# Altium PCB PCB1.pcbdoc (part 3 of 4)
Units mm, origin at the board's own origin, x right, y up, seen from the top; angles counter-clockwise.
Board outline 96.27 x 122.17 mm, 4 copper layers (Top Layer, Inner1, Inner2, Bottom Layer); 167 components, 166 nets, 783 pads, 353 vias.

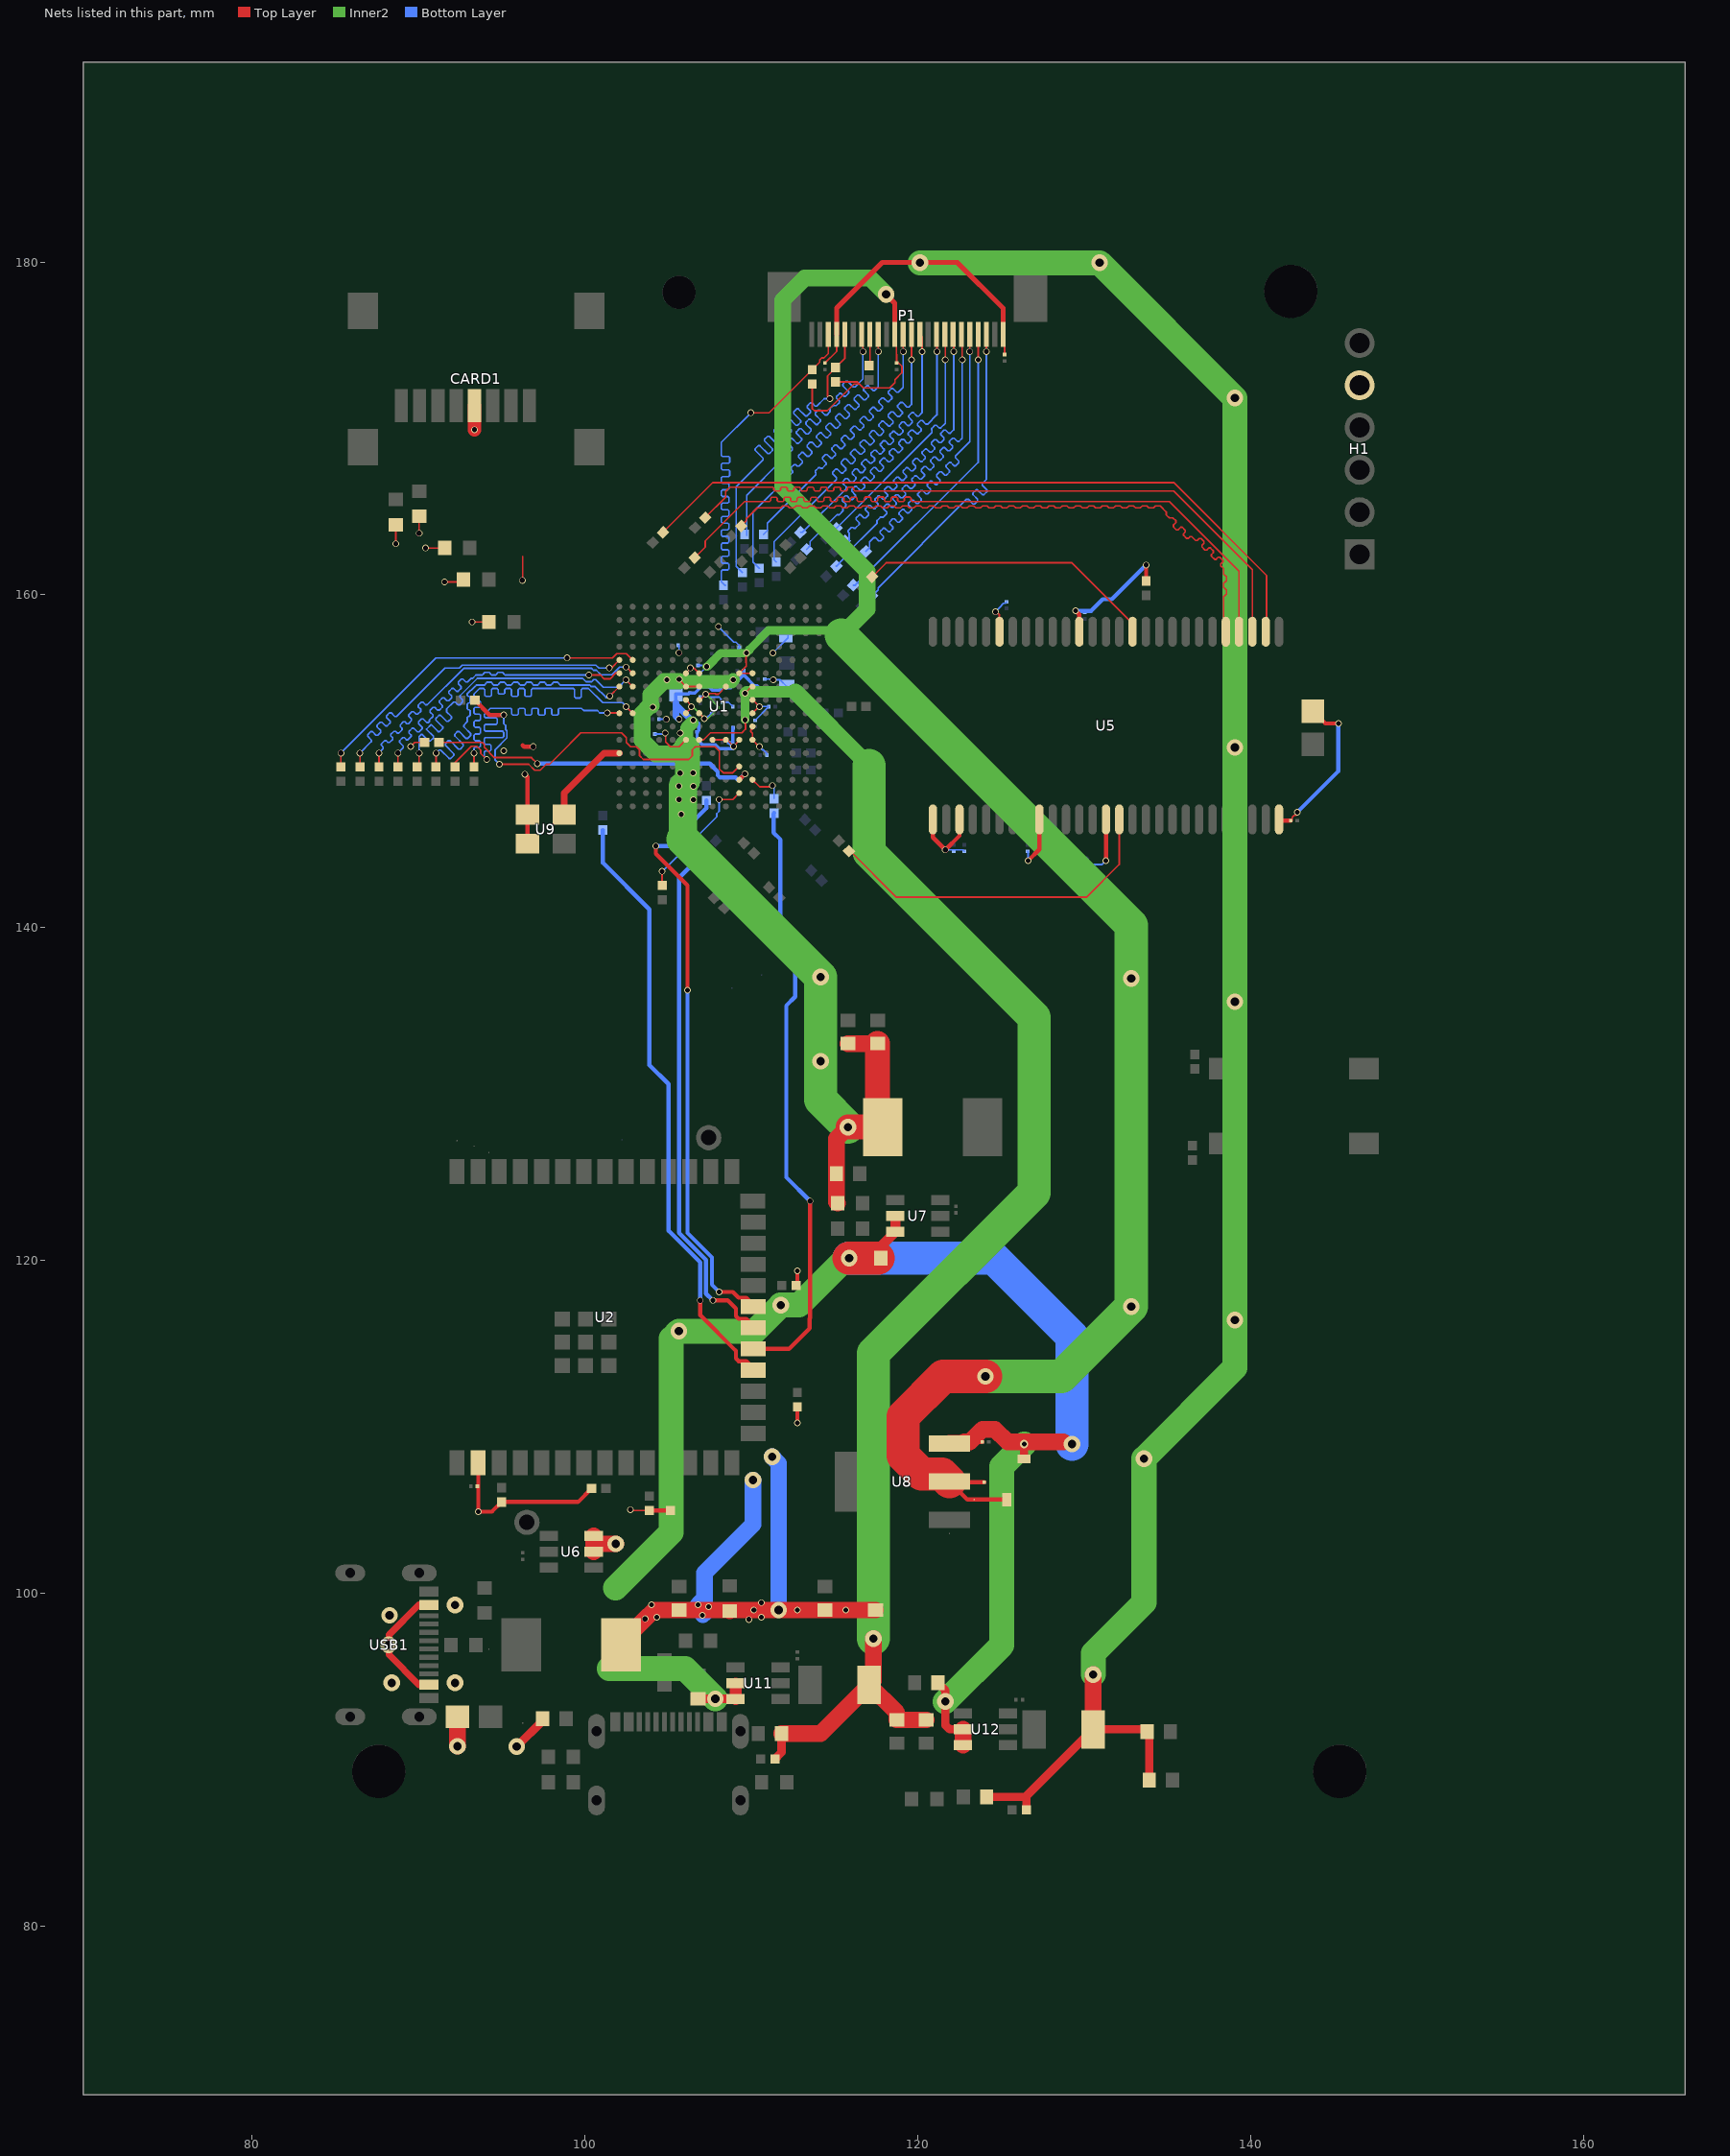
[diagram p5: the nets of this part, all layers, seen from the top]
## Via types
v1: diameter 0.4, hole 0.3, Top Layer to Bottom Layer, 318 vias
v2: diameter 1, hole 0.5, Top Layer to Bottom Layer, 34 vias
v3: diameter 0.5, hole 0.3, Top Layer to Bottom Layer, 1 vias

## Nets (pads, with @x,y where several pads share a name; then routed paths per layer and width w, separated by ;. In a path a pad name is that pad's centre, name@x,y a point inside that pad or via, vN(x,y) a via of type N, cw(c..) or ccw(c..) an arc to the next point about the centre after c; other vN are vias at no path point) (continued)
$1N75103: R65.1 U5.32 | length 40.7
  Top Layer w0.1: R65.1@109.399,164.136 109.706,164.443 109.706,164.57 110.363,165.227 111.775,165.227 111.902,165.354 112.175,165.354 112.302,165.227 112.575,165.227 112.702,165.354 112.975,165.354 113.102,165.227 113.375,165.227 113.502,165.354 113.775,165.354 113.902,165.227 114.175,165.227 114.302,165.354 114.575,165.354 114.702,165.227 114.975,165.227 115.102,165.354 115.375,165.354 115.502,165.227 115.775,165.227 115.902,165.354 116.175,165.354 116.302,165.227 116.575,165.227 116.702,165.354 116.975,165.354 117.102,165.227 117.375,165.227 117.502,165.354 117.775,165.354 117.902,165.227 118.175,165.227 118.302,165.354 118.575,165.354 118.702,165.227 118.975,165.227 119.102,165.354 119.375,165.354 119.502,165.227 119.775,165.227 119.902,165.354 120.175,165.354 120.302,165.227 120.575,165.227 120.702,165.354 120.975,165.354 121.102,165.227 121.375,165.227 121.502,165.354 121.775,165.354 121.902,165.227 122.175,165.227 122.302,165.354 122.575,165.354 122.702,165.227 122.975,165.227 123.102,165.354 123.375,165.354 123.502,165.227 123.775,165.227 123.902,165.354 124.175,165.354 124.302,165.227 124.575,165.227 124.702,165.354 124.975,165.354 125.102,165.227 125.375,165.227 125.502,165.354 125.775,165.354 125.902,165.227 126.175,165.227 126.302,165.354 126.575,165.354 126.702,165.227 126.975,165.227 127.102,165.354 127.375,165.354 127.502,165.227 127.775,165.227 127.902,165.354 128.175,165.354 128.302,165.227 128.575,165.227 128.702,165.354 128.975,165.354 129.102,165.227 129.375,165.227 129.502,165.354 129.775,165.354 129.902,165.227 130.175,165.227 130.302,165.354 130.575,165.354 130.702,165.227 130.975,165.227 131.102,165.354 131.375,165.354 131.502,165.227 131.775,165.227 131.902,165.354 132.175,165.354 132.302,165.227 132.575,165.227 132.702,165.354 132.975,165.354 133.102,165.227 133.375,165.227 133.502,165.354 133.775,165.354 133.902,165.227 134.175,165.227 134.302,165.354 134.575,165.354 134.947,164.982 134.947,164.803 135.13,164.62 135.23,164.62 135.242,164.632 135.342,164.632 135.525,164.449 135.525,164.349 135.371,164.195 135.371,164.095 135.553,163.912 135.653,163.912 135.808,164.066 135.908,164.066 136.091,163.883 136.091,163.783 135.985,163.678 135.985,163.578 136.168,163.395 136.268,163.395 136.373,163.501 136.473,163.501 136.707,163.267 136.807,163.267 136.926,163.386 137.026,163.386 137.208,163.203 137.208,163.103 137.09,162.984 137.09,162.884 137.272,162.702 137.372,162.702 137.491,162.82 137.591,162.82 137.774,162.638 137.774,162.538 137.655,162.419 137.655,162.319 137.838,162.136 137.938,162.136 138.057,162.255 138.157,162.255 138.34,162.072 138.34,161.972 138.221,161.853 138.221,161.753 138.391,161.583 138.391,161.243 138.462,161.172 138.486,161.172 138.557,161.101 138.557,160.843 138.486,160.772 138.462,160.772 138.391,160.701 138.391,160.443 138.462,160.372 138.486,160.372 138.557,160.301 138.557,160.043 138.486,159.972 138.462,159.972 138.391,159.901 138.391,157.915 U5.32@138.518,157.788
$1N75146: R66.1 U5.31 | length 43.6
  Top Layer w0.1: R66.1@106.605,162.231 107.235,162.861 107.235,163.242 109.601,165.608 111.096,165.608 111.167,165.679 111.167,165.791 111.237,165.862 111.496,165.862 111.567,165.791 111.567,165.679 111.637,165.608 111.896,165.608 111.967,165.679 111.967,165.791 112.037,165.862 112.296,165.862 112.367,165.791 112.367,165.679 112.437,165.608 112.696,165.608 112.767,165.679 112.767,165.791 112.837,165.862 113.096,165.862 113.167,165.791 113.167,165.679 113.237,165.608 113.496,165.608 113.567,165.679 113.567,165.791 113.637,165.862 113.896,165.862 113.967,165.791 113.967,165.679 114.037,165.608 114.296,165.608 114.367,165.679 114.367,165.791 114.437,165.862 114.696,165.862 114.767,165.791 114.767,165.679 114.837,165.608 115.096,165.608 115.167,165.679 115.167,165.791 115.237,165.862 115.496,165.862 115.567,165.791 115.567,165.679 115.637,165.608 115.896,165.608 115.967,165.679 115.967,165.791 116.037,165.862 116.296,165.862 116.367,165.791 116.367,165.679 116.437,165.608 116.732,165.608 116.803,165.679 116.803,165.809 116.874,165.879 117.132,165.879 117.203,165.809 117.203,165.679 117.274,165.608 117.532,165.608 117.603,165.679 117.603,165.809 117.674,165.879 117.932,165.879 118.003,165.809 118.003,165.679 118.074,165.608 118.332,165.608 118.403,165.679 118.403,165.809 118.474,165.879 118.732,165.879 118.803,165.809 118.803,165.679 118.874,165.608 119.132,165.608 119.203,165.679 119.203,165.809 119.274,165.879 119.532,165.879 119.603,165.809 119.603,165.679 119.674,165.608 135.128,165.608 139.318,161.418 U5.31@139.318,157.788
$1N75189: R67.1 U5.30 | length 41.4
  Top Layer w0.1: R67.1@107.24,164.644 108.458,165.862 108.458,166.214 108.712,166.468 111.296,166.468 111.367,166.397 111.367,166.314 111.438,166.243 111.696,166.243 111.767,166.314 111.767,166.397 111.838,166.468 112.096,166.468 112.167,166.397 112.167,166.314 112.238,166.243 112.496,166.243 112.567,166.314 112.567,166.397 112.638,166.468 112.896,166.468 112.967,166.397 112.967,166.314 113.038,166.243 113.296,166.243 113.367,166.314 113.367,166.397 113.438,166.468 113.696,166.468 113.767,166.397 113.767,166.314 113.838,166.243 114.096,166.243 114.167,166.314 114.167,166.397 114.238,166.468 114.496,166.468 114.567,166.397 114.567,166.314 114.638,166.243 114.896,166.243 114.967,166.314 114.967,166.397 115.038,166.468 115.296,166.468 115.367,166.397 115.367,166.314 115.438,166.243 115.696,166.243 115.767,166.314 115.767,166.397 115.838,166.468 116.096,166.468 116.167,166.397 116.167,166.314 116.238,166.243 135.382,166.243 140.118,161.507 U5.30@140.118,157.788
$1N75232: R68.1 U5.29 | length 43.2
  Top Layer w0.1: R68.1@104.7,163.755 107.696,166.751 135.382,166.751 140.97,161.163 140.97,157.84 U5.29@140.918,157.788
$1N75310: R69.2 U5.15 | length 20.9
  Top Layer w0.1: R69.2@115.876,144.601 115.965,144.601 118.735,141.831 130.147,141.831 132.118,143.802 U5.15@132.118,146.504
$1N75353: R70.1 U5.39 | length 18
  Top Layer w0.1: R70.1@117.273,161.088 118.11,161.925 129.27,161.925 132.918,158.277 U5.39@132.918,157.788
$1N78998: P1.7 R73.2 | length 21.8
  Top Layer w0.1: P1.7@116.634,175.655 116.713,175.577 v1(116.713,174.625)
  Bottom Layer w0.1: R73.2@109.728,163.576 109.728,165.989 111.898,168.159 111.898,168.259 111.589,168.568 111.589,168.668 111.772,168.851 111.872,168.851 112.181,168.542 112.281,168.542 112.464,168.725 112.464,168.825 112.155,169.134 112.155,169.234 112.337,169.417 112.437,169.417 112.747,169.108 112.847,169.108 113.029,169.29 113.029,169.39 112.72,169.7 112.72,169.8 112.903,169.982 113.003,169.982 113.312,169.673 113.412,169.673 113.595,169.856 113.595,169.956 113.286,170.265 113.286,170.365 113.469,170.548 113.569,170.548 113.878,170.239 113.978,170.239 114.161,170.422 114.161,170.522 113.852,170.831 113.852,170.931 114.035,171.114 114.135,171.114 114.444,170.805 114.544,170.805 114.73,170.991 114.73,171.184 114.917,171.37 115.109,171.37 115.292,171.553 115.292,171.653 115.126,171.819 115.126,171.919 115.309,172.102 115.409,172.102 115.575,171.936 115.675,171.936 115.858,172.119 115.858,172.219 115.513,172.563 115.513,172.663 115.696,172.846 115.796,172.846 116.141,172.502 116.241,172.502 116.713,172.974 v1(116.713,174.625)
$1N79046: P1.8 R35.1 | length 1.9
  Top Layer w0.1: R35.1@117.094,173.788 117.135,173.828 P1.8@117.135,175.655
$1N79086: P1.9 R75.2 | length 24.9
  Top Layer w0.1: v1(117.634,174.625) P1.9@117.634,175.655
  Bottom Layer w0.1: R75.2@110.49,161.596 110.109,161.977 110.109,164.973 112.485,167.349 112.485,167.449 112.395,167.54 112.395,167.64 112.578,167.823 112.678,167.823 112.768,167.732 112.868,167.732 113.079,167.943 113.079,168.043 112.848,168.274 112.848,168.374 113.031,168.557 113.131,168.557 113.362,168.326 113.462,168.326 113.645,168.509 113.645,168.609 113.364,168.89 113.364,168.99 113.547,169.173 113.647,169.173 113.928,168.892 114.028,168.892 114.211,169.075 114.211,169.175 113.93,169.456 113.93,169.556 114.113,169.739 114.213,169.739 114.494,169.458 114.594,169.458 114.776,169.64 114.776,169.74 114.495,170.021 114.495,170.121 114.678,170.304 114.778,170.304 115.059,170.023 115.159,170.023 115.342,170.206 115.342,170.306 115.061,170.587 115.061,170.687 115.244,170.87 115.344,170.87 115.625,170.589 115.725,170.589 115.908,170.772 115.908,170.872 115.627,171.153 115.627,171.253 115.81,171.436 115.91,171.436 116.191,171.155 116.291,171.155 116.474,171.338 116.474,171.438 116.193,171.719 116.193,171.819 116.375,172.001 116.475,172.001 116.756,171.72 116.856,171.72 117.039,171.903 117.039,172.003 116.758,172.284 116.758,172.384 116.941,172.567 117.041,172.567 117.322,172.286 117.422,172.286 117.634,172.498 v1(117.634,174.625)
$1N79129: P1.12 R76.2 | length 21.6
  Top Layer w0.1: v1(119.135,174.625) P1.12@119.135,175.655
  Bottom Layer w0.1: R76.2@110.744,163.628 110.977,163.861 110.977,164.317 113.889,167.229 113.889,167.329 113.862,167.356 113.862,167.456 114.045,167.639 114.145,167.639 114.172,167.612 114.272,167.612 114.498,167.838 114.498,167.938 114.281,168.156 114.281,168.256 114.464,168.439 114.564,168.439 114.781,168.221 114.881,168.221 115.064,168.404 115.064,168.504 114.846,168.721 114.846,168.821 115.029,169.004 115.129,169.004 115.347,168.787 115.447,168.787 115.63,168.97 115.63,169.07 115.412,169.287 115.412,169.387 115.595,169.57 115.695,169.57 115.913,169.353 116.013,169.353 116.195,169.535 116.195,169.635 115.978,169.853 115.978,169.953 116.161,170.136 116.261,170.136 116.478,169.918 116.578,169.918 116.761,170.101 116.761,170.201 116.544,170.419 116.544,170.519 116.726,170.701 116.826,170.701 117.044,170.484 117.144,170.484 117.327,170.667 117.327,170.767 117.109,170.984 117.109,171.084 117.292,171.267 117.392,171.267 117.61,171.05 117.71,171.05 117.892,171.232 117.892,171.332 117.675,171.55 117.675,171.65 117.858,171.833 117.958,171.833 118.175,171.615 118.275,171.615 118.458,171.798 118.458,171.898 118.241,172.116 118.241,172.216 118.423,172.398 118.523,172.398 118.741,172.181 118.841,172.181 119.135,172.475 v1(119.135,174.625)
$1N79172: P1.13 R77.2 | length 24.3
  Top Layer w0.1: v1(119.634,174.117) P1.13@119.634,175.655
  Bottom Layer w0.1: R77.2@111.506,161.977 111.379,162.104 111.379,163.195 115.124,166.94 115.124,167.04 114.893,167.271 114.893,167.371 115.076,167.554 115.176,167.554 115.407,167.323 115.507,167.323 115.69,167.506 115.69,167.606 115.409,167.887 115.409,167.987 115.592,168.17 115.692,168.17 115.973,167.889 116.073,167.889 116.255,168.071 116.255,168.171 115.974,168.452 115.974,168.552 116.157,168.735 116.257,168.735 116.538,168.454 116.638,168.454 116.821,168.637 116.821,168.737 116.54,169.018 116.54,169.118 116.723,169.301 116.823,169.301 117.104,169.02 117.204,169.02 117.387,169.203 117.387,169.303 117.106,169.584 117.106,169.684 117.289,169.867 117.389,169.867 117.67,169.586 117.77,169.586 117.952,169.768 117.952,169.868 117.671,170.149 117.671,170.249 117.854,170.432 117.954,170.432 118.235,170.151 118.335,170.151 118.518,170.334 118.518,170.434 118.237,170.715 118.237,170.815 118.42,170.998 118.52,170.998 118.801,170.717 118.901,170.717 119.084,170.9 119.084,171 118.803,171.281 118.803,171.381 118.986,171.564 119.086,171.564 119.367,171.283 119.467,171.283 119.634,171.45 v1(119.634,174.117)
$1N79215: P1.14 R78.2 | length 20.9
  Top Layer w0.1: P1.14@120.135,175.655 120.265,175.524 v1(120.265,174.621)
  Bottom Layer w0.1: R78.2@112.955,163.755 113.082,163.755 115.712,166.385 115.712,166.485 115.494,166.702 115.494,166.802 115.677,166.985 115.777,166.985 115.995,166.768 116.095,166.768 116.288,166.961 116.288,167.061 116.071,167.279 116.071,167.379 116.254,167.562 116.354,167.562 116.571,167.344 116.671,167.344 116.854,167.527 116.854,167.627 116.636,167.844 116.636,167.944 116.819,168.127 116.919,168.127 117.137,167.91 117.237,167.91 117.42,168.093 117.42,168.193 117.202,168.41 117.202,168.51 117.385,168.693 117.485,168.693 117.702,168.475 117.802,168.475 117.985,168.658 117.985,168.758 117.768,168.976 117.768,169.076 117.951,169.259 118.051,169.259 118.268,169.041 118.368,169.041 118.551,169.224 118.551,169.324 118.333,169.541 118.333,169.641 118.516,169.824 118.616,169.824 118.834,169.607 118.934,169.607 119.117,169.79 119.117,169.89 118.899,170.107 118.899,170.207 119.082,170.39 119.182,170.39 119.4,170.173 119.5,170.173 119.682,170.355 119.682,170.455 119.465,170.673 119.465,170.773 119.648,170.956 119.748,170.956 119.965,170.738 120.065,170.738 120.265,170.938 v1(120.265,174.621)
$1N79258: P1.16 R79.2 | length 22.8
  Top Layer w0.1: P1.16@121.134,175.654 121.158,175.63 v1(121.158,174.625)
  Bottom Layer w0.1: R79.2@113.336,162.739 113.544,162.947 113.544,163.201 115.153,164.81 115.295,164.81 115.507,165.022 115.507,165.164 115.692,165.349 115.692,165.449 115.475,165.667 115.475,165.767 115.657,165.949 115.757,165.949 115.975,165.732 116.075,165.732 116.258,165.915 116.258,166.015 116.04,166.232 116.04,166.332 116.223,166.515 116.323,166.515 116.541,166.298 116.641,166.298 116.823,166.48 116.823,166.58 116.606,166.798 116.606,166.898 116.789,167.081 116.889,167.081 117.106,166.863 117.206,166.863 117.389,167.046 117.389,167.146 117.172,167.364 117.172,167.464 117.354,167.646 117.454,167.646 117.672,167.429 117.772,167.429 117.955,167.612 117.955,167.712 117.737,167.929 117.737,168.029 117.92,168.212 118.02,168.212 118.238,167.995 118.338,167.995 118.52,168.177 118.52,168.277 118.303,168.495 118.303,168.595 118.486,168.778 118.586,168.778 118.803,168.56 118.903,168.56 119.086,168.743 119.086,168.843 118.869,169.061 118.869,169.161 119.051,169.343 119.151,169.343 119.369,169.126 119.469,169.126 119.652,169.309 119.652,169.409 119.434,169.626 119.434,169.726 119.617,169.909 119.717,169.909 119.935,169.692 120.035,169.692 120.217,169.874 120.217,169.974 120,170.192 120,170.292 120.183,170.475 120.283,170.475 120.5,170.257 120.6,170.257 121.158,170.815 v1(121.158,174.625)
$1N79301: P1.17 R80.2 | length 14.8
  Top Layer w0.1: P1.17@121.634,175.656 121.666,175.624 v1(121.666,174.117)
  Bottom Layer w0.1: R80.2@115.114,164.009 120.858,169.753 120.858,169.894 120.852,169.901 120.852,170.001 121.034,170.183 121.134,170.183 121.288,170.029 121.388,170.029 121.666,170.307 v1(121.666,174.117)
$1N79344: P1.18 R81.2 | length 21.7
  Top Layer w0.1: P1.18@122.134,175.655 122.174,175.615 v1(122.174,174.625)
  Bottom Layer w0.1: R81.2@115.881,163.246 115.881,163.727 115.835,163.772 115.835,163.872 116.018,164.055 116.118,164.055 116.164,164.01 116.264,164.01 116.493,164.239 116.493,164.339 116.307,164.524 116.307,164.624 116.49,164.807 116.59,164.807 116.775,164.621 116.875,164.621 117.058,164.804 117.058,164.904 116.873,165.09 116.873,165.19 117.056,165.372 117.156,165.372 117.341,165.187 117.441,165.187 117.624,165.37 117.624,165.47 117.439,165.655 117.439,165.755 117.621,165.938 117.721,165.938 117.907,165.753 118.007,165.753 118.19,165.936 118.19,166.036 118.004,166.221 118.004,166.321 118.187,166.504 118.287,166.504 118.472,166.318 118.572,166.318 118.755,166.501 118.755,166.601 118.57,166.787 118.57,166.887 118.753,167.07 118.853,167.07 119.038,166.884 119.138,166.884 119.321,167.067 119.321,167.167 119.136,167.352 119.136,167.452 119.318,167.635 119.418,167.635 119.604,167.45 119.704,167.45 119.887,167.633 119.887,167.733 119.701,167.918 119.701,168.018 119.884,168.201 119.984,168.201 120.169,168.016 120.269,168.016 120.452,168.198 120.452,168.298 120.267,168.484 120.267,168.584 120.45,168.767 120.55,168.767 120.735,168.581 120.835,168.581 121.018,168.764 121.018,168.864 120.833,169.049 120.833,169.149 121.016,169.332 121.116,169.332 121.301,169.147 121.401,169.147 121.584,169.33 121.584,169.43 121.398,169.615 121.398,169.715 121.581,169.898 121.681,169.898 121.867,169.713 121.967,169.713 122.174,169.92 v1(122.174,174.625)
$1N79387: P1.19 R82.2 | length 22.4
  Top Layer w0.1: P1.19@122.634,175.655 122.682,175.607 v1(122.682,174.117)
  Bottom Layer w0.1: R82.2@115.114,161.723 115.537,162.146 115.537,162.273 117.563,164.299 117.563,164.465 117.764,164.665 117.929,164.665 118.145,164.881 118.145,164.981 117.957,165.169 117.957,165.269 118.139,165.451 118.239,165.451 118.427,165.263 118.527,165.263 118.71,165.446 118.71,165.546 118.522,165.734 118.522,165.834 118.705,166.017 118.805,166.017 118.993,165.829 119.093,165.829 119.276,166.012 119.276,166.112 119.088,166.3 119.088,166.4 119.271,166.583 119.371,166.583 119.559,166.395 119.659,166.395 119.842,166.578 119.842,166.678 119.654,166.866 119.654,166.966 119.837,167.148 119.937,167.148 120.125,166.961 120.225,166.961 120.407,167.143 120.407,167.243 120.219,167.431 120.219,167.531 120.402,167.714 120.502,167.714 120.69,167.526 120.79,167.526 120.973,167.709 120.973,167.809 120.785,167.997 120.785,168.097 120.968,168.28 121.068,168.28 121.256,168.092 121.356,168.092 121.539,168.275 121.539,168.375 121.351,168.563 121.351,168.663 121.534,168.846 121.634,168.846 121.822,168.658 121.922,168.658 122.104,168.84 122.104,168.94 121.916,169.128 121.916,169.228 122.099,169.411 122.199,169.411 122.387,169.223 122.487,169.223 122.682,169.418 v1(122.682,174.117)
$1N79430: P1.20 R83.2 | length 21.7
  Top Layer w0.1: v1(123.136,174.625) P1.20@123.136,175.652
  Bottom Layer w0.1: R83.2@116.892,162.612 117.118,162.838 117.118,163.065 117.11,163.074 117.11,163.174 117.37,163.434 117.47,163.434 117.669,163.235 117.769,163.235 117.952,163.418 117.952,163.518 117.753,163.717 117.753,163.817 117.936,163.999 118.036,163.999 118.235,163.801 118.335,163.801 118.518,163.984 118.518,164.084 118.319,164.282 118.319,164.382 118.502,164.565 118.602,164.565 118.8,164.366 118.9,164.366 119.083,164.549 119.083,164.649 118.885,164.848 118.885,164.948 119.067,165.131 119.167,165.131 119.366,164.932 119.466,164.932 119.649,165.115 119.649,165.215 119.45,165.414 119.45,165.514 119.633,165.696 119.733,165.696 119.932,165.498 120.032,165.498 120.215,165.681 120.215,165.781 120.016,165.979 120.016,166.079 120.199,166.262 120.299,166.262 120.497,166.063 120.597,166.063 120.78,166.246 120.78,166.346 120.582,166.545 120.582,166.645 120.764,166.828 120.864,166.828 121.063,166.629 121.163,166.629 121.346,166.812 121.346,166.912 121.147,167.111 121.147,167.211 121.33,167.393 121.43,167.393 121.629,167.195 121.729,167.195 121.912,167.378 121.912,167.478 121.713,167.676 121.713,167.776 121.896,167.959 121.996,167.959 122.194,167.76 122.294,167.76 122.477,167.943 122.477,168.043 122.279,168.242 122.279,168.342 123.136,169.199 v1(123.136,174.625)
$1N79473: P1.21 R84.2 | length 18.3
  Top Layer w0.1: v1(123.636,174.117) P1.21@123.636,175.652
  Bottom Layer w0.1: R84.2@116.13,160.58 116.257,160.58 123.636,167.959 v1(123.636,174.117)
$1N79516: P1.22 R85.2 | length 20.4
  Top Layer w0.1: v1(124.136,174.625) P1.22@124.136,175.652
  Bottom Layer w0.1: R85.2@117.273,159.945 117.626,160.298 117.626,160.425 122.941,165.74 123.041,165.74 123.322,165.459 123.422,165.459 123.605,165.642 123.605,165.742 123.324,166.023 123.324,166.123 123.507,166.306 123.607,166.306 123.888,166.025 123.988,166.025 124.171,166.208 124.171,166.308 123.89,166.589 123.89,166.689 124.136,166.935 v1(124.136,174.625)
$1N79529: P1.3 R38.1 R71.2 | length 25.5
  Top Layer w0.1: v1(109.982,170.942) 111.073,170.942 R38.1@113.665,173.534 114.115,173.984 114.115,174.12 114.233,174.238 114.369,174.238 114.634,174.503 P1.3@114.634,175.655
  Bottom Layer w0.1: R71.2@108.458,160.58 108.406,160.58 108.204,160.782 108.204,161.431 108.275,161.502 108.591,161.502 108.662,161.573 108.662,161.831 108.591,161.902 108.275,161.902 108.204,161.973 108.204,162.242 108.275,162.313 108.591,162.313 108.662,162.383 108.662,162.642 108.591,162.713 108.275,162.713 108.204,162.783 108.204,163.042 108.275,163.113 108.591,163.113 108.662,163.183 108.662,163.442 108.591,163.513 108.275,163.513 108.204,163.583 108.204,163.842 108.275,163.913 108.591,163.913 108.662,163.983 108.662,164.242 108.591,164.313 108.275,164.313 108.204,164.383 108.204,164.642 108.275,164.713 108.591,164.713 108.662,164.783 108.662,165.042 108.591,165.113 108.275,165.113 108.204,165.183 108.204,165.442 108.275,165.513 108.591,165.513 108.662,165.583 108.662,165.842 108.591,165.913 108.275,165.913 108.204,165.983 108.204,166.242 108.275,166.313 108.591,166.313 108.662,166.383 108.662,166.642 108.591,166.713 108.275,166.713 108.204,166.783 108.204,167.042 108.275,167.113 108.641,167.113 108.712,167.183 108.712,167.442 108.641,167.513 108.275,167.513 108.204,167.583 108.204,167.842 108.275,167.913 108.641,167.913 108.712,167.983 108.712,168.242 108.641,168.313 108.275,168.313 108.204,168.383 108.204,169.164 v1(109.982,170.942)
$1N79537: P1.5 R39.1 R72.2 | length 25.1
  Top Layer w0.1: v1(114.724,171.788) 114.59,171.922 114.59,173.162 115.062,173.634 R39.1@115.062,173.661 115.634,174.233 P1.5@115.634,175.655
  Bottom Layer w0.1: R72.2@109.474,161.342 109.093,161.723 109.093,166.496 110.709,168.112 110.709,168.212 110.237,168.684 110.237,168.784 110.42,168.967 110.52,168.967 110.992,168.495 111.092,168.495 111.275,168.678 111.275,168.778 110.803,169.25 110.803,169.35 110.986,169.533 111.086,169.533 111.558,169.061 111.658,169.061 111.841,169.244 111.841,169.344 111.369,169.816 111.369,169.916 111.552,170.099 111.652,170.099 112.124,169.626 112.224,169.626 112.407,169.809 112.407,169.909 111.984,170.331 111.984,170.431 112.167,170.614 112.267,170.614 112.689,170.192 112.789,170.192 112.972,170.375 112.972,170.475 112.55,170.897 112.55,170.997 112.733,171.18 112.833,171.18 113.255,170.758 113.355,170.758 113.561,170.963 113.561,171.063 113.371,171.253 113.371,171.353 113.554,171.536 113.654,171.536 113.844,171.346 113.944,171.346 114.385,171.788 v1(114.724,171.788)
$1N79556: R6.2 U2.19 | length 36.3
  Top Layer w0.254: U2.19@110.114,114.681 112.268,114.681 113.507,115.92 113.507,116.516 113.538,116.547 v1(113.538,123.571)
  Bottom Layer w0.254: R6.2@111.379,146.887 111.335,146.843 111.335,145.713 111.76,145.288 111.76,139.319 112.649,138.43 112.649,135.852 112.112,135.315 112.112,124.997 v1(113.538,123.571)
$1N79602: R86.2 U2.18 | length 36.5
  Top Layer w0.254: v1(106.934,117.602) 106.934,116.718 109.085,114.567 109.085,114.115 109.248,113.952 109.7,113.952 U2.18@110.241,113.411
  Bottom Layer w0.254: R86.2@101.092,145.871 101.092,143.891 103.886,141.097 103.886,131.743 105.029,130.6 105.029,121.793 106.934,119.888 v1(106.934,117.602)
$1N79645: R87.2 U2.20 | length 32
  Top Layer w0.254: v1(107.696,117.602) 108.59,117.602 109.085,117.107 109.085,116.655 109.248,116.492 109.7,116.492 U2.20@110.241,115.951
  Bottom Layer w0.254: R87.2@107.263,144.601 105.664,143.002 105.664,121.659 107.288,120.035 107.288,118.01 v1(107.696,117.602)
$1N79688: R88.2 U2.21 | length 35.4
  Top Layer w0.254: v1(104.267,144.907) 104.267,144.441 106.172,142.536 v1(106.172,136.242) ; v1(108.077,118.11) 108.9,118.11 109.248,117.762 109.7,117.762 U2.21@110.241,117.221
  Bottom Layer w0.254: v1(104.267,144.907) 105.029,144.907 107.315,147.193 R88.2@107.315,147.649 ; v1(106.172,136.242) 106.172,121.651 107.642,120.181 107.642,118.545 v1(108.077,118.11)
$2N5507: R23.2 U1.P10 | length 20.1
  Top Layer w0.1: R23.2@91.238,151.13 93.853,151.13 93.959,151.024 93.959,150.836 94.575,150.22 96.795,150.22 v1(97.155,149.86)
  Top Layer w0.254: U1.P10@109.277,148.889 109.601,149.213 v1@109.601,149.225
  Bottom Layer w0.254: v1(97.155,149.86) 107.507,149.86 107.986,149.381 107.986,149.159 108.127,149.018 109.073,149.018 109.173,148.918 109.294,148.918 v1(109.622,149.246)
$2N5509: R24.2 U1.N10 | length 24
  Top Layer w0.1: v1(94.869,149.818) 96.628,149.818 96.988,149.458 97.322,149.458 97.682,149.818 97.875,149.818 99.119,151.062 99.119,151.067 99.759,151.707 102.199,151.707 102.495,151.411 102.495,151.131 102.755,150.871 103.091,150.871 103.295,150.667 103.295,150.331 103.519,150.107 105.435,150.107 105.442,150.114 105.912,150.114 105.919,150.107 106.235,150.107 106.459,150.331 106.459,150.689 106.641,150.871 107.835,150.871 108.095,150.611 108.095,149.531 108.319,149.307 108.895,149.307 U1.N10@109.277,149.689
  Top Layer w0.254: R24.2@93.397,153.67 94.286,152.781 v1(95.123,152.781)
  Bottom Layer w0.1: v1(94.869,149.818) 94.615,150.072 94.615,150.697 95.323,151.405 95.323,151.829 95.25,151.902 95.25,152.146 95.123,152.273 v1(95.123,152.781)
$2N5511: R25.2 U1.R10 | length 7.9
  Top Layer w0.1: R25.2@104.648,142.546 v1(104.648,143.383) ; v1(108.077,147.701) 108.889,147.701 U1.R10@109.277,148.089
  Bottom Layer w0.1: v1(104.648,143.383) 107.929,146.664 107.929,146.852 108.077,147 v1(108.077,147.701)
+1V1: C25.2 C27.2 C28.2 C41.1 C42.1 C43.1 C44.1 C49.1 C53.1 C54.1 C61.1 L2.2 R15.2 U1.G6 U1.G7 U1.L8 U1.L9 U1.L10 | length 72.3
  Top Layer w0.1: v1@105.664,154.94 105.664,154.902 U1.G6@106.077,154.489 U1.G7@106.877,154.489 ; U1.L8@107.677,151.289 U1.L9@108.477,151.289 108.543,151.289 v1(108.936,150.897) 109.277,151.238 U1.L10@109.277,151.289
  Top Layer w1: R15.2@115.198,123.444 115.124,123.518 C25.2@115.124,125.222 115.124,127.316 v2(115.824,128.016) ; C27.2@115.824,133.031 C28.2@117.602,133.031
  Top Layer w1.5: v2(115.824,128.016) L2.2@117.904,128.016 117.602,128.318 C28.2@117.602,133.031
  Inner2 w0.8: 105.324,150.439 105.744,150.859 106.125,150.859 106.125,151.99 v1@106.436,152.302 ; v1@105.672,154.909 105.777,154.805 106.053,154.805 106.069,154.789 108.815,154.789 v1(108.92,154.894)
  Inner2 w1: 103.823,153.258 103.442,152.877 103.442,151.239 104.242,150.439 105.324,150.439 ; v1@104.012,153.352 103.95,153.413 103.95,154.002 104.757,154.809 v1@105.672,154.809
  Inner2 w1.5: 105.895,148.508 106.172,148.785 106.172,150.812 106.125,150.859
  Inner2 w1.7: 105.895,145.311 105.895,148.508
  Inner2 w2: 105.895,145.311 v2(114.173,137.033) v2(114.173,131.972) 114.173,129.667 v2(115.824,128.016)
  Bottom Layer w0.2: 105.475,153.518 C61.1@105.475,154.051 106.24,154.051 C41.1@106.299,154.11 106.607,154.11 106.986,154.489 107.461,154.489 107.661,154.289 108.082,154.289 C42.1@108.342,154.548 108.458,154.432 108.78,154.432 109.542,155.194 ; v1(106.514,152.479) 106.642,152.479 106.736,152.385 106.736,152.381 106.842,152.275 106.842,151.859 C54.1@106.748,151.765 106.748,151.316 107.061,151.003 107.819,151.003 108.073,150.749 108.788,150.749 108.801,150.762 v1@108.936,150.762 ; C53.1@108.653,151.13 108.78,151.003 108.839,151.003 108.907,150.935 C49.1@108.907,152.019 ; C43.1@109.542,155.448 109.542,155.194 ; C44.1@110.558,154.178 110.525,154.211 110.525,154.392 110.377,154.54 110.196,154.54 109.542,155.194
  Bottom Layer w0.4: 105.475,153.409 106.405,152.479 v1(106.514,152.479) ; 105.475,153.518 105.475,152.716 v1(105.666,152.525)
  other v1: 105.791,146.812 105.664,147.701 106.527,147.689 106.526,148.489 105.661,148.508 105.726,149.289 106.508,149.306 105.727,151.69 104.086,153.249 104.926,154.888 105.672,154.932
+1V8: C29.1 C32.2 C35.1 C62.1 C63.1 P1.11 pad.55@123.394,105.627 R38.2 R39.2 U1.F10 U1.F11 U8.2 | length 132.8
  Top Layer w0.1: v1(109.709,156.504) 109.709,156.262 109.695,156.247 109.695,155.931 109.709,155.917 109.709,155.721 U1.F10@109.277,155.289 U1.F11@110.077,155.289 ; R38.2@113.665,172.668 113.665,172.205 113.661,172.201 113.661,171.2 113.792,171.069 114.574,171.069 116.173,172.668 116.509,172.668 ; R39.2@115.062,172.795 116.382,172.795 116.509,172.668 ; P1.11@118.634,175.655 118.733,175.557 118.733,174.458 118.745,174.446 C35.1@118.745,173.931 ; 118.856,173.931 119.057,173.73 119.057,173.352 118.639,172.934 118.639,172.756 118.321,172.437 116.74,172.437 116.509,172.668
  Top Layer w0.254: C29.1@124.011,106.68 121.943,106.68 122.996,105.627 pad.55@123.394,105.627 C32.2@125.349,105.627
  Top Layer w0.3: v2(118.11,178.054) 118.634,177.53 P1.11@118.634,175.655
  Top Layer w2: U8.2@121.914,106.709 121.459,107.163 120.24,107.163 119.126,108.277 119.126,110.617 121.539,113.03 v2(124.079,113.03)
  Inner2 w0.5: v1(107.325,155.689) 107.362,155.689 108.178,156.504 v1(109.709,156.504) 109.888,156.683 109.888,156.713 111.036,157.861 115.379,157.861
  Inner2 w1: 115.411,157.575 116.967,159.131 116.967,161.417 111.887,166.497 111.887,177.71 113.21,179.033 117.131,179.033 v2(118.11,178.054)
  Inner2 w2: 115.411,157.575 132.842,140.144 v2(132.842,136.952) v2(132.842,117.221) 128.651,113.03 v2(124.079,113.03)
  Bottom Layer w0.1: C63.1@106.807,155.761 107.253,155.761 v1(107.325,155.689) 106.934,155.298 C62.1@106.934,155.262
+2V5: C65.2 C67.2 C68.2 L3.2 R41.2 U1.G11 U1.L7 | length 91.3
  Top Layer w0.1: U1.L7@106.877,151.289 107.137,151.289 107.555,151.707 109.435,151.707 109.659,151.931 109.659,152.247 109.629,152.277 v1(109.629,152.489) ; v1(109.629,154.089) 110.029,154.489 U1.G11@110.077,154.489
  Top Layer w0.5: R41.2@111.431,90.043 111.825,90.437 C65.2@111.825,91.567
  Top Layer w1: C65.2@111.825,91.567 114.17,91.567 L3.2@117.091,94.488 ; v2(117.345,97.282) 117.345,94.742 L3.2@117.091,94.488 ; C67.2@120.523,92.394 C68.2@118.745,92.394 118.745,92.834 L3.2@117.091,94.488
  Inner2 w0.5: v1(109.629,152.489) v1(109.629,154.089)
  Inner2 w0.7: v1(109.629,154.089) 109.718,154.178 112.649,154.178
  Inner2 w1: 112.649,154.178 117.091,149.736
  Inner2 w1.5: v2(117.345,97.282) v2@117.348,97.285
  Inner2 w2: 117.091,149.736 117.091,144.529 127,134.62 127,124.079 117.348,114.427 v2@117.348,97.285
+2V8: C34.1 C70.2 C72.2 C73.2 C74.1 L4.2 P1.4 P1.24 R47.2 | length 139.5
  Top Layer w0.1: C34.1@114.427,173.931 115.135,174.639 P1.4@115.135,175.655 ; P1.24@125.136,175.652 125.222,175.566 C74.1@125.222,174.439
  Top Layer w0.3: P1.4@115.135,175.655 115.135,177.23 117.885,179.98 122.383,179.98 125.136,177.227 P1.24@125.136,175.652
  Top Layer w0.5: C70.2@124.144,87.757 126.489,87.757 ; R47.2@126.544,86.995 126.544,87.702 126.489,87.757 ; C73.2@133.793,91.694 133.666,91.821 L4.2@130.553,91.821 126.489,87.757 ; C72.2@133.92,88.773 C73.2@133.92,91.567
  Top Layer w1: L4.2@130.556,91.824 v2(130.556,95.123)
  Inner2 w1.5: v2(120.142,179.959) v2(130.937,179.959) v2(139.065,171.831) v2(139.065,150.833) v2(139.065,135.548) v2(139.065,116.414) 139.065,113.552 v2(133.604,108.091) 133.604,99.441 130.556,96.393 v2(130.556,95.123)
+3V3: C8.1 C10.1 C11.1 C12.1 C13.1 C14.1 C15.2 C16.2 C17.2 C19.2 C22.2 C23.2 C37.1 C39.1 C40.1 C45.1 C46.1 C47.1 C48.1 C50.1 C51.1 C52.1 C55.1 C56.1 C57.1 C58.1 C59.1 CARD1.4 H1.5 L1.2 R1.2 R3.1 R4.1 R5.2 R7.2 R11.2 R16.2 R17.2 R18.2 R19.2 R20.2 R21.2 R22.2 R23.1 U1.F6 U1.F7 U1.G9 U1.H6 U1.H7 U1.H11 U1.J6 U1.J7 U1.J11 U1.K11 U1.L6 U1.L11 U2.2 U5.1 U5.3 U5.9 U5.14 U5.27 U5.43 U5.49 U9.1 U9.4 | length 123
  Top Layer w0.1: v1(88.646,163.068) R19.2@88.646,164.22 ; v1(89.537,150.887) 89.78,151.13 R23.1@90.372,151.13 ; v1(90.043,163.703) R18.2@90.043,164.728 ; v1(90.424,162.814) R20.2@91.576,162.814 ; v1(91.567,160.782) 92.592,160.782 R17.2@92.719,160.909 ; v1(93.218,158.369) R16.2@94.243,158.369 ; v1@96.275,160.909 96.275,162.306 ; v1(102.743,105.029) 102.795,104.977 R21.2@103.886,104.977 ; v1(104.829,151.689) 104.859,151.659 104.859,151.167 105.15,150.876 105.664,150.876 U1.L6@106.077,151.289 ; U1.J6@106.077,152.889 106.405,153.217 v1(106.405,153.288) 106.405,153.361 U1.H6@106.077,153.689 ; U1.F6@106.077,155.289 106.345,155.557 v1(106.345,155.607) 106.559,155.607 U1.F7@106.877,155.289 ; U1.J7@106.877,152.889 107.188,152.578 v1@107.188,152.527 ; U1.H7@106.877,153.689 106.926,153.689 v1(107.274,154.037) 107.484,154.037 107.519,154.071 107.835,154.071 107.881,154.025 108.013,154.025 U1.G9@108.477,154.489 ; U1.K11@110.077,152.089 110.077,151.962 109.982,151.867 109.982,151.765 110.077,151.67 U1.L11@110.077,151.289 v1(110.49,150.876) ; U1.J11@110.077,152.889 110.477,153.289 v1(110.49,153.289) 110.09,153.689 U1.H11@110.077,153.689 ; v1(124.674,158.977) 124.741,158.977 124.918,158.8 U5.49@124.918,157.788 ; C14.1@142.426,146.431 142.509,146.514 142.509,146.625 142.627,146.743 142.738,146.743 142.816,146.821 v1(142.816,146.939)
  Top Layer w0.254: U2.2@93.721,107.836 93.599,107.714 v1(93.599,104.902) 94.413,104.902 R7.2@94.996,105.485 99.591,105.485 R5.2@100.405,106.299 ; 96.271,150.952 96.346,150.876 v1(96.901,150.876) ; v1(96.393,149.225) 96.563,149.055 U9.4@96.563,146.798 U9.1@96.563,145.048 ; R21.2@103.886,104.977 R22.2@105.156,104.977 ; R3.1@112.701,118.491 112.776,118.566 v1(112.776,119.38) ; v1(112.776,110.236) R4.1@112.776,111.2 ; U5.1@120.918,146.631 120.918,145.422 v1(121.666,144.674) 122.518,145.526 U5.3@122.518,146.504 ; v1(126.638,144.028) 127.318,144.707 U5.9@127.318,146.504 ; v1(129.5,159.044) 129.718,158.826 U5.43@129.718,157.788 ; v1(131.318,144.018) U5.14@131.318,146.504 ; R1.2@133.731,160.834 v1(133.731,161.798) ; U5.27@141.718,146.504 141.791,146.431 C14.1@142.426,146.431 ; C8.1@143.764,153.019 144.51,152.273 v1(145.288,152.273)
  Top Layer w0.8: v1(93.372,169.926) CARD1.4@93.372,171.374
  Top Layer w1: L1.2@102.187,96.901 102.187,97.028 v1(103.622,98.463) 104.154,98.995 C19.2@105.664,98.995 108.659,98.995 R11.2@108.712,98.942 108.765,98.995 v1(110.161,98.995) v2(111.647,98.995) v1(112.775,98.995) C23.2@114.427,98.995 v1(115.692,98.995) C22.2@117.475,98.995
  Inner2 w0.1: v1(106.405,153.288) 106.468,153.288 v1(107.188,152.568) 107.412,152.568 108.041,153.198 108.041,153.269 v1(107.274,154.037)
  Bottom Layer w0.1: C51.1@104.208,151.638 104.778,151.638 v1(104.829,151.689) ; C56.1@104.462,152.527 104.886,152.527 v1(104.894,152.519) ; C37.1@105.605,156.972 105.664,156.913 v1(105.664,156.524) ; C45.1@106.934,153.865 107.102,153.865 v1(107.274,154.037) 107.455,153.855 108.071,153.855 108.189,153.737 108.189,153.626 C46.1@108.272,153.543 108.644,153.543 C47.1@108.898,153.289 ; v1(107.188,152.568) 107.288,152.568 C57.1@107.628,152.908 ; C50.1@108.018,156.464 109.018,156.464 109.205,156.651 109.205,156.762 C39.1@109.288,156.845 109.288,156.956 109.087,157.157 108.961,157.157 v1(108.029,158.089) ; C52.1@110.236,152.468 C55.1@111.057,153.289 v1(110.49,153.289) ; v1(110.49,150.876) 110.686,150.68 110.738,150.68 110.939,150.479 C48.1@110.939,150.368 ; C40.1@110.812,154.94 111.274,154.94 v1(111.323,154.89) 111.745,154.89 C59.1@112.141,154.494 ; v1(111.301,156.512) 112.206,157.417 C58.1@112.206,157.607 ; v1(121.666,144.674) 121.974,144.674 121.98,144.668 122.726,144.668 C11.1@122.809,144.585 ; v1(124.674,158.977) 125.037,159.34 125.037,159.379 125.155,159.497 125.266,159.497 C16.2@125.349,159.58 ; C12.1@126.619,144.585 126.638,144.566 v1(126.638,144.028) ; C13.1@129.91,143.88 130.028,143.88 130.106,143.802 131.102,143.802 v1(131.318,144.018)
  Bottom Layer w0.254: v1(129.5,159.044) 130.427,159.044 131.12,159.737 131.67,159.737 v1(133.731,161.798) ; v1(142.816,146.939) 145.288,149.411 v1(145.288,152.273)
  Bottom Layer w1: v1(106.807,99.314) 107.188,99.695 ; v1@107.092,98.71 107.188,98.806 107.188,99.695 ; v2(110.109,106.807) 110.109,104.14 107.188,101.219 107.188,99.695 ; v2(111.252,108.204) 111.647,107.809 v2(111.647,98.995)
  other v1: 109.855,98.425 104.329,98.552 110.617,98.552 107.061,98.679 107.442,99.187 104.013,99.314 110.617,99.441 95.123,150.636 96.241,160.876
+5V: C20.2 C26.2 C30.1 C31.2 C33.2 C66.2 C71.2 U6.2 U6.3 U7.2 U7.3 U8.3 U11.2 U11.3 U12.2 U12.3 USB1.A4B9 USB1.B4A9 | length 111.1
  Top Layer w0.254: U8.3@123.137,109.093 C30.1@123.884,109.093
  Top Layer w0.4: USB1.B4A9@90.627,94.501 90.03,94.501 88.227,96.304 88.227,97.508 90.02,99.301 USB1.A4B9@90.627,99.301
  Top Layer w0.5: v2(95.904,90.786) 97.471,92.353 C20.2@97.471,92.456 ; C66.2@106.807,93.661 v2(107.842,93.661) 109.042,93.661 U11.3@109.066,93.637 ; C71.2@121.223,94.615 121.666,94.172 v2(121.666,93.492) 121.666,92.075 121.92,91.821 U12.2@122.729,91.821 ; C31.2@126.402,108.077 v3(126.402,108.966)
  Top Layer w0.6: C26.2@117.791,120.142 117.791,120.858 U7.3@118.665,121.732 U7.2@118.665,122.682
  Top Layer w0.7: U11.3@109.066,93.637 U11.2@109.066,94.587
  Top Layer w1: v2(92.345,90.805) C33.2@92.345,92.583 ; U6.2@100.537,102.491 100.537,102.97 ; U6.3@100.537,103.439 100.537,102.97 ; v2(101.854,102.97) 100.537,102.97 ; U8.3@121.914,109.009 122.725,109.009 122.809,109.093 123.137,109.093 123.899,109.855 124.649,109.855 125.411,109.093 128.751,109.093 ; U12.3@122.729,90.871 U12.2@122.729,91.819
  Top Layer w2: v2(115.886,120.142) C26.2@117.639,120.142
  Inner2 w1.5: 101.473,95.463 106.04,95.463 v2(107.842,93.661) ; 101.854,100.33 105.197,103.673 105.197,115.302 v2(105.65,115.755) 110.21,115.755 v2(111.77,117.315) 112.87,117.315 115.697,120.142 v2(115.886,120.142) ; v2(121.666,93.492) 125.062,96.888 125.062,107.626 v3(126.402,108.966)
  Bottom Layer w2: v2(115.886,120.142) 124.587,120.142 129.286,115.443 v2(129.286,108.966)
  other v2: 88.392,94.615 92.202,94.615 88.213,96.901 88.265,98.679 92.202,99.301
CCLK: R6.1 U1.P11 | length 2.2
  Top Layer w0.1: U1.P11@110.077,148.889 110.503,148.463 110.711,148.463 110.719,148.471 111.212,148.471 v1(111.277,148.537)
  Bottom Layer w0.1: v1(111.277,148.537) 111.379,148.435 R6.1@111.379,147.753
CRYSTAL: U1.M1 U9.3 | length 5.6
  Top Layer w0.4: U9.3@98.763,146.798 98.763,148.087 101.162,150.485 101.209,150.485 101.213,150.489 U1.M1@102.077,150.489
D0: R26.1 U1.E2 | length 21
  Top Layer w0.1: R26.1@85.344,149.658 v1(85.344,150.495) ; v1@98.933,156.21 101.658,156.21 101.919,156.471 102.495,156.471 U1.E2@102.877,156.089
  Bottom Layer w0.1: v1(85.344,150.495) 91.059,156.21 v1(98.943,156.21)
D1: R27.1 U1.E1 | length 21.1
  Top Layer w0.1: R27.1@86.487,149.658 v1(86.487,150.495) ; v1(101.473,155.604) 101.592,155.604 U1.E1@102.077,156.089
  Bottom Layer w0.1: v1(86.487,150.495) 87.172,151.18 87.172,151.28 86.955,151.498 86.955,151.598 87.137,151.78 87.237,151.78 87.455,151.563 87.555,151.563 87.738,151.746 87.738,151.846 87.52,152.063 87.52,152.163 87.703,152.346 87.803,152.346 88.021,152.129 88.121,152.129 88.303,152.311 88.303,152.411 88.086,152.629 88.086,152.729 88.269,152.912 88.369,152.912 88.586,152.694 88.686,152.694 91.596,155.604 92.456,155.604 92.634,155.782 100.666,155.782 100.844,155.604 v1(101.473,155.604)
D2: R28.1 U1.F2 | length 21
  Top Layer w0.1: R28.1@87.63,149.658 v1(87.63,150.495) ; v1(102.486,155.659) 102.507,155.659 U1.F2@102.877,155.289
  Bottom Layer w0.1: v1(87.63,150.495) 87.884,150.749 87.884,150.849 87.78,150.953 87.78,151.053 87.963,151.236 88.063,151.236 88.167,151.132 88.267,151.132 88.45,151.315 88.45,151.415 88.346,151.519 88.346,151.619 88.529,151.802 88.629,151.802 88.733,151.698 88.833,151.698 89.015,151.88 89.015,151.98 88.911,152.084 88.911,152.184 89.094,152.367 89.194,152.367 89.298,152.263 89.398,152.263 89.581,152.446 89.581,152.546 89.427,152.7 89.427,152.8 89.61,152.983 89.71,152.983 89.864,152.829 89.964,152.829 90.147,153.012 90.147,153.112 89.993,153.266 89.993,153.366 90.176,153.549 90.276,153.549 90.43,153.395 90.53,153.395 92.717,155.582 100.414,155.582 100.524,155.473 100.692,155.473 100.963,155.202 101.64,155.202 102.096,155.659 v1(102.486,155.659)
D3: R29.1 U1.F1 | length 21
  Top Layer w0.1: R29.1@88.773,149.658 v1(88.773,150.495) ; v1(100.248,155.18) 100.947,155.18 101.179,154.948 101.513,154.948 101.871,155.306 102.06,155.306 U1.F1@102.077,155.289
  Bottom Layer w0.1: v1(88.773,150.495) 89.092,150.814 89.092,150.914 88.875,151.132 88.875,151.232 89.058,151.415 89.158,151.415 89.277,151.295 89.377,151.295 89.56,151.478 89.56,151.578 89.44,151.697 89.44,151.797 89.623,151.98 89.723,151.98 89.941,151.763 90.041,151.763 90.224,151.946 90.224,152.046 90.006,152.263 90.006,152.363 90.189,152.546 90.289,152.546 90.507,152.329 90.607,152.329 90.659,152.381 90.659,152.477 90.871,152.69 90.871,152.79 90.702,152.959 90.702,153.059 90.885,153.242 90.985,153.242 91.154,153.072 91.254,153.072 91.437,153.255 91.437,153.355 91.268,153.525 91.268,153.625 91.45,153.807 91.55,153.807 91.72,153.638 91.82,153.638 92.003,153.821 92.003,153.921 91.833,154.09 91.833,154.19 92.016,154.373 92.116,154.373 92.285,154.204 92.385,154.204 92.568,154.387 92.568,154.487 92.399,154.656 92.399,154.756 92.582,154.939 92.682,154.939 92.851,154.769 92.951,154.769 93.16,154.978 93.256,154.978 93.458,155.18 93.853,155.18 93.924,155.251 93.924,155.277 93.995,155.348 94.253,155.348 94.324,155.277 94.324,155.251 94.395,155.18 94.653,155.18 94.724,155.251 94.724,155.277 94.795,155.348 95.053,155.348 95.124,155.277 95.124,155.251 95.195,155.18 v1(100.248,155.18)
D4: R30.1 U1.G2 | length 21
  Top Layer w0.1: R30.1@89.916,149.658 90.043,149.785 v1(90.043,150.495) ; v1(102.471,154.892) 102.474,154.892 U1.G2@102.877,154.489
  Bottom Layer w0.1: v1(90.043,150.495) 90.043,151.482 90.189,151.628 90.207,151.628 90.619,151.216 90.719,151.216 90.902,151.399 90.902,151.499 90.49,151.911 90.49,151.929 90.755,152.194 90.773,152.194 91.185,151.782 91.285,151.782 91.468,151.965 91.468,152.065 91.056,152.477 91.056,152.577 91.239,152.76 91.339,152.76 91.701,152.398 91.801,152.398 91.983,152.581 91.983,152.681 91.694,152.97 91.694,153.133 92.12,153.559 92.22,153.559 92.388,153.391 92.488,153.391 92.671,153.573 92.671,153.673 92.503,153.842 92.503,153.942 93.541,154.98 99.879,154.98 100.081,154.778 100.414,154.778 100.541,154.905 100.65,154.905 101.102,154.453 102.031,154.453 v1(102.471,154.892)
D5: R31.1 U1.G1 | length 21
  Top Layer w0.1: R31.1@91.059,149.658 v1(91.059,150.495) ; v1(101.507,153.924) 101.512,153.924 U1.G1@102.077,154.489
  Bottom Layer w0.1: v1(91.059,150.495) 91.238,150.674 91.338,150.674 91.847,150.165 91.947,150.165 92.13,150.348 92.13,150.448 91.621,150.957 91.621,151.057 91.803,151.239 91.903,151.239 92.413,150.73 92.513,150.73 92.695,150.913 92.695,151.013 92.186,151.522 92.186,151.622 92.35,151.786 92.45,151.786 92.862,151.374 92.962,151.374 93.145,151.556 93.145,151.656 92.733,152.069 92.733,152.169 92.933,152.369 92.933,152.627 93.004,152.697 93.045,152.697 93.116,152.768 93.116,153.027 93.045,153.097 93.004,153.097 92.933,153.168 92.933,153.427 93.004,153.497 93.045,153.497 93.116,153.568 93.116,153.827 93.045,153.897 93.004,153.897 92.933,153.968 92.933,154.042 93.379,154.488 93.401,154.488 93.491,154.578 93.976,154.578 94.047,154.649 94.047,154.68 94.118,154.751 94.376,154.751 94.447,154.68 94.447,154.649 94.518,154.578 94.776,154.578 94.847,154.649 94.847,154.68 94.918,154.751 95.176,154.751 95.247,154.68 95.247,154.649 95.318,154.578 95.576,154.578 95.647,154.649 95.647,154.68 95.718,154.751 95.976,154.751 96.047,154.68 96.047,154.649 96.118,154.578 96.376,154.578 96.447,154.649 96.447,154.68 96.518,154.751 96.776,154.751 96.847,154.68 96.847,154.649 96.918,154.578 97.176,154.578 97.247,154.649 97.247,154.68 97.318,154.751 97.576,154.751 97.647,154.68 97.647,154.649 97.718,154.578 97.976,154.578 98.047,154.649 98.047,154.68 98.118,154.751 98.376,154.751 98.447,154.68 98.447,154.649 98.518,154.578 100.302,154.578 100.392,154.488 100.621,154.488 101.275,153.834 101.417,153.834 v1(101.507,153.924)
D6: R32.1 U1.J1 | length 20.9
  Top Layer w0.1: R32.1@92.202,149.658 92.202,149.921 93.178,150.897 93.512,150.897 93.747,150.662 93.747,150.474 v1(94.107,150.114) ; v1(101.346,152.908) 102.058,152.908 U1.J1@102.077,152.889
  Bottom Layer w0.1: v1(94.107,150.114) 93.959,150.262 93.959,150.546 94.03,150.617 94.294,150.617 94.365,150.687 94.365,150.946 94.294,151.017 94.03,151.017 93.959,151.087 93.959,151.346 94.03,151.417 95.052,151.417 95.123,151.487 95.123,151.746 95.052,151.817 94.03,151.817 93.959,151.887 93.959,152.146 94.03,152.217 94.671,152.217 94.742,152.287 94.742,152.546 94.671,152.617 94.03,152.617 93.959,152.687 93.959,152.821 94.321,153.183 95.539,153.183 95.61,153.112 95.61,152.852 95.68,152.781 95.939,152.781 96.01,152.852 96.01,153.112 96.08,153.183 96.339,153.183 96.41,153.112 96.41,152.852 96.48,152.781 96.739,152.781 96.81,152.852 96.81,153.112 96.88,153.183 97.139,153.183 97.21,153.112 97.21,152.852 97.28,152.781 97.539,152.781 97.61,152.852 97.61,153.112 97.68,153.183 97.939,153.183 98.01,153.112 98.01,152.852 98.08,152.781 98.339,152.781 98.41,152.852 98.41,153.112 98.48,153.183 99.801,153.183 99.928,153.056 100.751,153.056 100.899,152.908 v1(101.346,152.908)
D7: R34.1 U1.J2 | length 21
  Top Layer w0.1: R34.1@93.345,149.658 v1(93.345,150.495) ; v1(102.489,153.289) 102.489,153.277 U1.J2@102.877,152.889
  Bottom Layer w0.1: v1(93.345,150.495) 93.345,150.769 93.416,150.84 93.659,150.84 93.73,150.911 93.73,151.169 93.659,151.24 93.416,151.24 93.345,151.311 93.345,151.569 93.416,151.64 93.659,151.64 93.73,151.711 93.73,151.969 93.659,152.04 93.416,152.04 93.345,152.111 93.345,152.369 93.416,152.44 93.659,152.44 93.73,152.511 93.73,152.769 93.659,152.84 93.416,152.84 93.345,152.911 93.345,153.169 93.416,153.24 93.659,153.24 93.73,153.311 93.73,153.569 93.659,153.64 93.416,153.64 93.345,153.711 93.345,154.051 93.672,154.378 93.921,154.378 93.991,154.307 93.991,153.969 94.062,153.898 94.321,153.898 94.391,153.969 94.391,154.307 94.462,154.378 94.721,154.378 94.791,154.307 94.791,154.11 94.862,154.04 95.121,154.04 95.191,154.11 95.191,154.307 95.262,154.378 95.521,154.378 95.591,154.307 95.591,153.969 95.662,153.898 95.921,153.898 95.991,153.969 95.991,154.307 96.062,154.378 96.321,154.378 96.391,154.307 96.391,153.969 96.462,153.898 96.721,153.898 96.791,153.969 96.791,154.307 96.862,154.378 99.316,154.378 99.386,154.307 99.386,153.868 99.457,153.797 99.716,153.797 99.786,153.868 99.786,154.307 99.857,154.378 100.22,154.378 101.076,153.522 102.256,153.522 v1(102.489,153.289)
